VERSION 5.7 ;
BUSBITCHARS "[]" ;
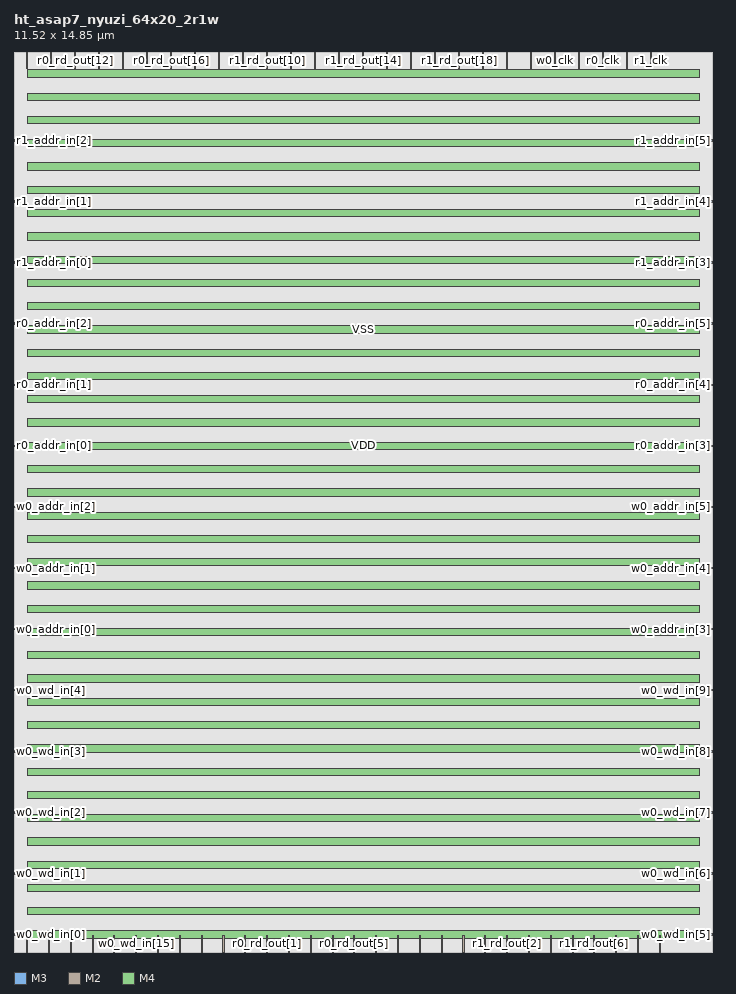
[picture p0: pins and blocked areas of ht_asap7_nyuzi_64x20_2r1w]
MACRO ht_asap7_nyuzi_64x20_2r1w
  FOREIGN ht_asap7_nyuzi_64x20_2r1w 0 0 ;
  SYMMETRY X Y R90 ;
  SIZE 11.520 BY 14.850 ;
  CLASS BLOCK ;
  PIN w0_wd_in[0]
    DIRECTION INPUT ;
    USE SIGNAL ;
    SHAPE ABUTMENT ;
    PORT
      LAYER M3 ;
      RECT 0.000 0.276 0.072 0.300 ;
    END
  END w0_wd_in[0]
  PIN w0_wd_in[1]
    DIRECTION INPUT ;
    USE SIGNAL ;
    SHAPE ABUTMENT ;
    PORT
      LAYER M3 ;
      RECT 0.000 1.284 0.072 1.308 ;
    END
  END w0_wd_in[1]
  PIN w0_wd_in[2]
    DIRECTION INPUT ;
    USE SIGNAL ;
    SHAPE ABUTMENT ;
    PORT
      LAYER M3 ;
      RECT 0.000 2.292 0.072 2.316 ;
    END
  END w0_wd_in[2]
  PIN w0_wd_in[3]
    DIRECTION INPUT ;
    USE SIGNAL ;
    SHAPE ABUTMENT ;
    PORT
      LAYER M3 ;
      RECT 0.000 3.300 0.072 3.324 ;
    END
  END w0_wd_in[3]
  PIN w0_wd_in[4]
    DIRECTION INPUT ;
    USE SIGNAL ;
    SHAPE ABUTMENT ;
    PORT
      LAYER M3 ;
      RECT 0.000 4.308 0.072 4.332 ;
    END
  END w0_wd_in[4]
  PIN w0_wd_in[5]
    DIRECTION INPUT ;
    USE SIGNAL ;
    SHAPE ABUTMENT ;
    PORT
      LAYER M3 ;
      RECT 11.448 0.276 11.520 0.300 ;
    END
  END w0_wd_in[5]
  PIN w0_wd_in[6]
    DIRECTION INPUT ;
    USE SIGNAL ;
    SHAPE ABUTMENT ;
    PORT
      LAYER M3 ;
      RECT 11.448 1.284 11.520 1.308 ;
    END
  END w0_wd_in[6]
  PIN w0_wd_in[7]
    DIRECTION INPUT ;
    USE SIGNAL ;
    SHAPE ABUTMENT ;
    PORT
      LAYER M3 ;
      RECT 11.448 2.292 11.520 2.316 ;
    END
  END w0_wd_in[7]
  PIN w0_wd_in[8]
    DIRECTION INPUT ;
    USE SIGNAL ;
    SHAPE ABUTMENT ;
    PORT
      LAYER M3 ;
      RECT 11.448 3.300 11.520 3.324 ;
    END
  END w0_wd_in[8]
  PIN w0_wd_in[9]
    DIRECTION INPUT ;
    USE SIGNAL ;
    SHAPE ABUTMENT ;
    PORT
      LAYER M3 ;
      RECT 11.448 4.308 11.520 4.332 ;
    END
  END w0_wd_in[9]
  PIN w0_wd_in[10]
    DIRECTION INPUT ;
    USE SIGNAL ;
    SHAPE ABUTMENT ;
    PORT
      LAYER M2 ;
      RECT 0.207 0.000 0.225 0.270 ;
    END
  END w0_wd_in[10]
  PIN w0_wd_in[11]
    DIRECTION INPUT ;
    USE SIGNAL ;
    SHAPE ABUTMENT ;
    PORT
      LAYER M2 ;
      RECT 0.567 0.000 0.585 0.270 ;
    END
  END w0_wd_in[11]
  PIN w0_wd_in[12]
    DIRECTION INPUT ;
    USE SIGNAL ;
    SHAPE ABUTMENT ;
    PORT
      LAYER M2 ;
      RECT 0.927 0.000 0.945 0.270 ;
    END
  END w0_wd_in[12]
  PIN w0_wd_in[13]
    DIRECTION INPUT ;
    USE SIGNAL ;
    SHAPE ABUTMENT ;
    PORT
      LAYER M2 ;
      RECT 1.287 0.000 1.305 0.270 ;
    END
  END w0_wd_in[13]
  PIN w0_wd_in[14]
    DIRECTION INPUT ;
    USE SIGNAL ;
    SHAPE ABUTMENT ;
    PORT
      LAYER M2 ;
      RECT 1.647 0.000 1.665 0.270 ;
    END
  END w0_wd_in[14]
  PIN w0_wd_in[15]
    DIRECTION INPUT ;
    USE SIGNAL ;
    SHAPE ABUTMENT ;
    PORT
      LAYER M2 ;
      RECT 2.007 0.000 2.025 0.270 ;
    END
  END w0_wd_in[15]
  PIN w0_wd_in[16]
    DIRECTION INPUT ;
    USE SIGNAL ;
    SHAPE ABUTMENT ;
    PORT
      LAYER M2 ;
      RECT 2.367 0.000 2.385 0.270 ;
    END
  END w0_wd_in[16]
  PIN w0_wd_in[17]
    DIRECTION INPUT ;
    USE SIGNAL ;
    SHAPE ABUTMENT ;
    PORT
      LAYER M2 ;
      RECT 2.727 0.000 2.745 0.270 ;
    END
  END w0_wd_in[17]
  PIN w0_wd_in[18]
    DIRECTION INPUT ;
    USE SIGNAL ;
    SHAPE ABUTMENT ;
    PORT
      LAYER M2 ;
      RECT 3.087 0.000 3.105 0.270 ;
    END
  END w0_wd_in[18]
  PIN w0_wd_in[19]
    DIRECTION INPUT ;
    USE SIGNAL ;
    SHAPE ABUTMENT ;
    PORT
      LAYER M2 ;
      RECT 3.447 0.000 3.465 0.270 ;
    END
  END w0_wd_in[19]
  PIN r0_rd_out[0]
    DIRECTION OUTPUT ;
    USE SIGNAL ;
    SHAPE ABUTMENT ;
    PORT
      LAYER M2 ;
      RECT 3.807 0.000 3.825 0.270 ;
    END
  END r0_rd_out[0]
  PIN r0_rd_out[1]
    DIRECTION OUTPUT ;
    USE SIGNAL ;
    SHAPE ABUTMENT ;
    PORT
      LAYER M2 ;
      RECT 4.167 0.000 4.185 0.270 ;
    END
  END r0_rd_out[1]
  PIN r0_rd_out[2]
    DIRECTION OUTPUT ;
    USE SIGNAL ;
    SHAPE ABUTMENT ;
    PORT
      LAYER M2 ;
      RECT 4.527 0.000 4.545 0.270 ;
    END
  END r0_rd_out[2]
  PIN r0_rd_out[3]
    DIRECTION OUTPUT ;
    USE SIGNAL ;
    SHAPE ABUTMENT ;
    PORT
      LAYER M2 ;
      RECT 4.887 0.000 4.905 0.270 ;
    END
  END r0_rd_out[3]
  PIN r0_rd_out[4]
    DIRECTION OUTPUT ;
    USE SIGNAL ;
    SHAPE ABUTMENT ;
    PORT
      LAYER M2 ;
      RECT 5.247 0.000 5.265 0.270 ;
    END
  END r0_rd_out[4]
  PIN r0_rd_out[5]
    DIRECTION OUTPUT ;
    USE SIGNAL ;
    SHAPE ABUTMENT ;
    PORT
      LAYER M2 ;
      RECT 5.607 0.000 5.625 0.270 ;
    END
  END r0_rd_out[5]
  PIN r0_rd_out[6]
    DIRECTION OUTPUT ;
    USE SIGNAL ;
    SHAPE ABUTMENT ;
    PORT
      LAYER M2 ;
      RECT 5.967 0.000 5.985 0.270 ;
    END
  END r0_rd_out[6]
  PIN r0_rd_out[7]
    DIRECTION OUTPUT ;
    USE SIGNAL ;
    SHAPE ABUTMENT ;
    PORT
      LAYER M2 ;
      RECT 6.327 0.000 6.345 0.270 ;
    END
  END r0_rd_out[7]
  PIN r0_rd_out[8]
    DIRECTION OUTPUT ;
    USE SIGNAL ;
    SHAPE ABUTMENT ;
    PORT
      LAYER M2 ;
      RECT 6.687 0.000 6.705 0.270 ;
    END
  END r0_rd_out[8]
  PIN r0_rd_out[9]
    DIRECTION OUTPUT ;
    USE SIGNAL ;
    SHAPE ABUTMENT ;
    PORT
      LAYER M2 ;
      RECT 7.047 0.000 7.065 0.270 ;
    END
  END r0_rd_out[9]
  PIN r0_rd_out[10]
    DIRECTION OUTPUT ;
    USE SIGNAL ;
    SHAPE ABUTMENT ;
    PORT
      LAYER M2 ;
      RECT 0.207 14.580 0.225 14.850 ;
    END
  END r0_rd_out[10]
  PIN r0_rd_out[11]
    DIRECTION OUTPUT ;
    USE SIGNAL ;
    SHAPE ABUTMENT ;
    PORT
      LAYER M2 ;
      RECT 0.603 14.580 0.621 14.850 ;
    END
  END r0_rd_out[11]
  PIN r0_rd_out[12]
    DIRECTION OUTPUT ;
    USE SIGNAL ;
    SHAPE ABUTMENT ;
    PORT
      LAYER M2 ;
      RECT 0.999 14.580 1.017 14.850 ;
    END
  END r0_rd_out[12]
  PIN r0_rd_out[13]
    DIRECTION OUTPUT ;
    USE SIGNAL ;
    SHAPE ABUTMENT ;
    PORT
      LAYER M2 ;
      RECT 1.395 14.580 1.413 14.850 ;
    END
  END r0_rd_out[13]
  PIN r0_rd_out[14]
    DIRECTION OUTPUT ;
    USE SIGNAL ;
    SHAPE ABUTMENT ;
    PORT
      LAYER M2 ;
      RECT 1.791 14.580 1.809 14.850 ;
    END
  END r0_rd_out[14]
  PIN r0_rd_out[15]
    DIRECTION OUTPUT ;
    USE SIGNAL ;
    SHAPE ABUTMENT ;
    PORT
      LAYER M2 ;
      RECT 2.187 14.580 2.205 14.850 ;
    END
  END r0_rd_out[15]
  PIN r0_rd_out[16]
    DIRECTION OUTPUT ;
    USE SIGNAL ;
    SHAPE ABUTMENT ;
    PORT
      LAYER M2 ;
      RECT 2.583 14.580 2.601 14.850 ;
    END
  END r0_rd_out[16]
  PIN r0_rd_out[17]
    DIRECTION OUTPUT ;
    USE SIGNAL ;
    SHAPE ABUTMENT ;
    PORT
      LAYER M2 ;
      RECT 2.979 14.580 2.997 14.850 ;
    END
  END r0_rd_out[17]
  PIN r0_rd_out[18]
    DIRECTION OUTPUT ;
    USE SIGNAL ;
    SHAPE ABUTMENT ;
    PORT
      LAYER M2 ;
      RECT 3.375 14.580 3.393 14.850 ;
    END
  END r0_rd_out[18]
  PIN r0_rd_out[19]
    DIRECTION OUTPUT ;
    USE SIGNAL ;
    SHAPE ABUTMENT ;
    PORT
      LAYER M2 ;
      RECT 3.771 14.580 3.789 14.850 ;
    END
  END r0_rd_out[19]
  PIN r1_rd_out[0]
    DIRECTION OUTPUT ;
    USE SIGNAL ;
    SHAPE ABUTMENT ;
    PORT
      LAYER M2 ;
      RECT 7.407 0.000 7.425 0.270 ;
    END
  END r1_rd_out[0]
  PIN r1_rd_out[1]
    DIRECTION OUTPUT ;
    USE SIGNAL ;
    SHAPE ABUTMENT ;
    PORT
      LAYER M2 ;
      RECT 7.767 0.000 7.785 0.270 ;
    END
  END r1_rd_out[1]
  PIN r1_rd_out[2]
    DIRECTION OUTPUT ;
    USE SIGNAL ;
    SHAPE ABUTMENT ;
    PORT
      LAYER M2 ;
      RECT 8.127 0.000 8.145 0.270 ;
    END
  END r1_rd_out[2]
  PIN r1_rd_out[3]
    DIRECTION OUTPUT ;
    USE SIGNAL ;
    SHAPE ABUTMENT ;
    PORT
      LAYER M2 ;
      RECT 8.487 0.000 8.505 0.270 ;
    END
  END r1_rd_out[3]
  PIN r1_rd_out[4]
    DIRECTION OUTPUT ;
    USE SIGNAL ;
    SHAPE ABUTMENT ;
    PORT
      LAYER M2 ;
      RECT 8.847 0.000 8.865 0.270 ;
    END
  END r1_rd_out[4]
  PIN r1_rd_out[5]
    DIRECTION OUTPUT ;
    USE SIGNAL ;
    SHAPE ABUTMENT ;
    PORT
      LAYER M2 ;
      RECT 9.207 0.000 9.225 0.270 ;
    END
  END r1_rd_out[5]
  PIN r1_rd_out[6]
    DIRECTION OUTPUT ;
    USE SIGNAL ;
    SHAPE ABUTMENT ;
    PORT
      LAYER M2 ;
      RECT 9.567 0.000 9.585 0.270 ;
    END
  END r1_rd_out[6]
  PIN r1_rd_out[7]
    DIRECTION OUTPUT ;
    USE SIGNAL ;
    SHAPE ABUTMENT ;
    PORT
      LAYER M2 ;
      RECT 9.927 0.000 9.945 0.270 ;
    END
  END r1_rd_out[7]
  PIN r1_rd_out[8]
    DIRECTION OUTPUT ;
    USE SIGNAL ;
    SHAPE ABUTMENT ;
    PORT
      LAYER M2 ;
      RECT 10.287 0.000 10.305 0.270 ;
    END
  END r1_rd_out[8]
  PIN r1_rd_out[9]
    DIRECTION OUTPUT ;
    USE SIGNAL ;
    SHAPE ABUTMENT ;
    PORT
      LAYER M2 ;
      RECT 10.647 0.000 10.665 0.270 ;
    END
  END r1_rd_out[9]
  PIN r1_rd_out[10]
    DIRECTION OUTPUT ;
    USE SIGNAL ;
    SHAPE ABUTMENT ;
    PORT
      LAYER M2 ;
      RECT 4.167 14.580 4.185 14.850 ;
    END
  END r1_rd_out[10]
  PIN r1_rd_out[11]
    DIRECTION OUTPUT ;
    USE SIGNAL ;
    SHAPE ABUTMENT ;
    PORT
      LAYER M2 ;
      RECT 4.563 14.580 4.581 14.850 ;
    END
  END r1_rd_out[11]
  PIN r1_rd_out[12]
    DIRECTION OUTPUT ;
    USE SIGNAL ;
    SHAPE ABUTMENT ;
    PORT
      LAYER M2 ;
      RECT 4.959 14.580 4.977 14.850 ;
    END
  END r1_rd_out[12]
  PIN r1_rd_out[13]
    DIRECTION OUTPUT ;
    USE SIGNAL ;
    SHAPE ABUTMENT ;
    PORT
      LAYER M2 ;
      RECT 5.355 14.580 5.373 14.850 ;
    END
  END r1_rd_out[13]
  PIN r1_rd_out[14]
    DIRECTION OUTPUT ;
    USE SIGNAL ;
    SHAPE ABUTMENT ;
    PORT
      LAYER M2 ;
      RECT 5.751 14.580 5.769 14.850 ;
    END
  END r1_rd_out[14]
  PIN r1_rd_out[15]
    DIRECTION OUTPUT ;
    USE SIGNAL ;
    SHAPE ABUTMENT ;
    PORT
      LAYER M2 ;
      RECT 6.147 14.580 6.165 14.850 ;
    END
  END r1_rd_out[15]
  PIN r1_rd_out[16]
    DIRECTION OUTPUT ;
    USE SIGNAL ;
    SHAPE ABUTMENT ;
    PORT
      LAYER M2 ;
      RECT 6.543 14.580 6.561 14.850 ;
    END
  END r1_rd_out[16]
  PIN r1_rd_out[17]
    DIRECTION OUTPUT ;
    USE SIGNAL ;
    SHAPE ABUTMENT ;
    PORT
      LAYER M2 ;
      RECT 6.939 14.580 6.957 14.850 ;
    END
  END r1_rd_out[17]
  PIN r1_rd_out[18]
    DIRECTION OUTPUT ;
    USE SIGNAL ;
    SHAPE ABUTMENT ;
    PORT
      LAYER M2 ;
      RECT 7.335 14.580 7.353 14.850 ;
    END
  END r1_rd_out[18]
  PIN r1_rd_out[19]
    DIRECTION OUTPUT ;
    USE SIGNAL ;
    SHAPE ABUTMENT ;
    PORT
      LAYER M2 ;
      RECT 7.731 14.580 7.749 14.850 ;
    END
  END r1_rd_out[19]
  PIN w0_addr_in[0]
    DIRECTION INPUT ;
    USE SIGNAL ;
    SHAPE ABUTMENT ;
    PORT
      LAYER M3 ;
      RECT 0.000 5.316 0.072 5.340 ;
    END
  END w0_addr_in[0]
  PIN w0_addr_in[1]
    DIRECTION INPUT ;
    USE SIGNAL ;
    SHAPE ABUTMENT ;
    PORT
      LAYER M3 ;
      RECT 0.000 6.324 0.072 6.348 ;
    END
  END w0_addr_in[1]
  PIN w0_addr_in[2]
    DIRECTION INPUT ;
    USE SIGNAL ;
    SHAPE ABUTMENT ;
    PORT
      LAYER M3 ;
      RECT 0.000 7.332 0.072 7.356 ;
    END
  END w0_addr_in[2]
  PIN w0_addr_in[3]
    DIRECTION INPUT ;
    USE SIGNAL ;
    SHAPE ABUTMENT ;
    PORT
      LAYER M3 ;
      RECT 11.448 5.316 11.520 5.340 ;
    END
  END w0_addr_in[3]
  PIN w0_addr_in[4]
    DIRECTION INPUT ;
    USE SIGNAL ;
    SHAPE ABUTMENT ;
    PORT
      LAYER M3 ;
      RECT 11.448 6.324 11.520 6.348 ;
    END
  END w0_addr_in[4]
  PIN w0_addr_in[5]
    DIRECTION INPUT ;
    USE SIGNAL ;
    SHAPE ABUTMENT ;
    PORT
      LAYER M3 ;
      RECT 11.448 7.332 11.520 7.356 ;
    END
  END w0_addr_in[5]
  PIN r0_addr_in[0]
    DIRECTION INPUT ;
    USE SIGNAL ;
    SHAPE ABUTMENT ;
    PORT
      LAYER M3 ;
      RECT 0.000 8.340 0.072 8.364 ;
    END
  END r0_addr_in[0]
  PIN r0_addr_in[1]
    DIRECTION INPUT ;
    USE SIGNAL ;
    SHAPE ABUTMENT ;
    PORT
      LAYER M3 ;
      RECT 0.000 9.348 0.072 9.372 ;
    END
  END r0_addr_in[1]
  PIN r0_addr_in[2]
    DIRECTION INPUT ;
    USE SIGNAL ;
    SHAPE ABUTMENT ;
    PORT
      LAYER M3 ;
      RECT 0.000 10.356 0.072 10.380 ;
    END
  END r0_addr_in[2]
  PIN r0_addr_in[3]
    DIRECTION INPUT ;
    USE SIGNAL ;
    SHAPE ABUTMENT ;
    PORT
      LAYER M3 ;
      RECT 11.448 8.340 11.520 8.364 ;
    END
  END r0_addr_in[3]
  PIN r0_addr_in[4]
    DIRECTION INPUT ;
    USE SIGNAL ;
    SHAPE ABUTMENT ;
    PORT
      LAYER M3 ;
      RECT 11.448 9.348 11.520 9.372 ;
    END
  END r0_addr_in[4]
  PIN r0_addr_in[5]
    DIRECTION INPUT ;
    USE SIGNAL ;
    SHAPE ABUTMENT ;
    PORT
      LAYER M3 ;
      RECT 11.448 10.356 11.520 10.380 ;
    END
  END r0_addr_in[5]
  PIN r1_addr_in[0]
    DIRECTION INPUT ;
    USE SIGNAL ;
    SHAPE ABUTMENT ;
    PORT
      LAYER M3 ;
      RECT 0.000 11.364 0.072 11.388 ;
    END
  END r1_addr_in[0]
  PIN r1_addr_in[1]
    DIRECTION INPUT ;
    USE SIGNAL ;
    SHAPE ABUTMENT ;
    PORT
      LAYER M3 ;
      RECT 0.000 12.372 0.072 12.396 ;
    END
  END r1_addr_in[1]
  PIN r1_addr_in[2]
    DIRECTION INPUT ;
    USE SIGNAL ;
    SHAPE ABUTMENT ;
    PORT
      LAYER M3 ;
      RECT 0.000 13.380 0.072 13.404 ;
    END
  END r1_addr_in[2]
  PIN r1_addr_in[3]
    DIRECTION INPUT ;
    USE SIGNAL ;
    SHAPE ABUTMENT ;
    PORT
      LAYER M3 ;
      RECT 11.448 11.364 11.520 11.388 ;
    END
  END r1_addr_in[3]
  PIN r1_addr_in[4]
    DIRECTION INPUT ;
    USE SIGNAL ;
    SHAPE ABUTMENT ;
    PORT
      LAYER M3 ;
      RECT 11.448 12.372 11.520 12.396 ;
    END
  END r1_addr_in[4]
  PIN r1_addr_in[5]
    DIRECTION INPUT ;
    USE SIGNAL ;
    SHAPE ABUTMENT ;
    PORT
      LAYER M3 ;
      RECT 11.448 13.380 11.520 13.404 ;
    END
  END r1_addr_in[5]
  PIN w0_we_in
    DIRECTION INPUT ;
    USE SIGNAL ;
    SHAPE ABUTMENT ;
    PORT
      LAYER M2 ;
      RECT 8.127 14.580 8.145 14.850 ;
    END
  END w0_we_in
  PIN w0_ce_in
    DIRECTION INPUT ;
    USE SIGNAL ;
    SHAPE ABUTMENT ;
    PORT
      LAYER M2 ;
      RECT 8.523 14.580 8.541 14.850 ;
    END
  END w0_ce_in
  PIN w0_clk
    DIRECTION INPUT ;
    USE SIGNAL ;
    SHAPE ABUTMENT ;
    PORT
      LAYER M2 ;
      RECT 8.919 14.580 8.937 14.850 ;
    END
  END w0_clk
  PIN r0_ce_in
    DIRECTION INPUT ;
    USE SIGNAL ;
    SHAPE ABUTMENT ;
    PORT
      LAYER M2 ;
      RECT 9.315 14.580 9.333 14.850 ;
    END
  END r0_ce_in
  PIN r0_clk
    DIRECTION INPUT ;
    USE SIGNAL ;
    SHAPE ABUTMENT ;
    PORT
      LAYER M2 ;
      RECT 9.711 14.580 9.729 14.850 ;
    END
  END r0_clk
  PIN r1_ce_in
    DIRECTION INPUT ;
    USE SIGNAL ;
    SHAPE ABUTMENT ;
    PORT
      LAYER M2 ;
      RECT 10.107 14.580 10.125 14.850 ;
    END
  END r1_ce_in
  PIN r1_clk
    DIRECTION INPUT ;
    USE SIGNAL ;
    SHAPE ABUTMENT ;
    PORT
      LAYER M2 ;
      RECT 10.503 14.580 10.521 14.850 ;
    END
  END r1_clk
  PIN VSS
    DIRECTION INOUT ;
    USE GROUND ;
    PORT
      LAYER M4 ;
      RECT 0.216 0.228 11.304 0.348 ;
      RECT 0.216 0.996 11.304 1.116 ;
      RECT 0.216 1.764 11.304 1.884 ;
      RECT 0.216 2.532 11.304 2.652 ;
      RECT 0.216 3.300 11.304 3.420 ;
      RECT 0.216 4.068 11.304 4.188 ;
      RECT 0.216 4.836 11.304 4.956 ;
      RECT 0.216 5.604 11.304 5.724 ;
      RECT 0.216 6.372 11.304 6.492 ;
      RECT 0.216 7.140 11.304 7.260 ;
      RECT 0.216 7.908 11.304 8.028 ;
      RECT 0.216 8.676 11.304 8.796 ;
      RECT 0.216 9.444 11.304 9.564 ;
      RECT 0.216 10.212 11.304 10.332 ;
      RECT 0.216 10.980 11.304 11.100 ;
      RECT 0.216 11.748 11.304 11.868 ;
      RECT 0.216 12.516 11.304 12.636 ;
      RECT 0.216 13.284 11.304 13.404 ;
      RECT 0.216 14.052 11.304 14.172 ;
    END
  END VSS
  PIN VDD
    DIRECTION INOUT ;
    USE POWER ;
    PORT
      LAYER M4 ;
      RECT 0.216 0.612 11.304 0.732 ;
      RECT 0.216 1.380 11.304 1.500 ;
      RECT 0.216 2.148 11.304 2.268 ;
      RECT 0.216 2.916 11.304 3.036 ;
      RECT 0.216 3.684 11.304 3.804 ;
      RECT 0.216 4.452 11.304 4.572 ;
      RECT 0.216 5.220 11.304 5.340 ;
      RECT 0.216 5.988 11.304 6.108 ;
      RECT 0.216 6.756 11.304 6.876 ;
      RECT 0.216 7.524 11.304 7.644 ;
      RECT 0.216 8.292 11.304 8.412 ;
      RECT 0.216 9.060 11.304 9.180 ;
      RECT 0.216 9.828 11.304 9.948 ;
      RECT 0.216 10.596 11.304 10.716 ;
      RECT 0.216 11.364 11.304 11.484 ;
      RECT 0.216 12.132 11.304 12.252 ;
      RECT 0.216 12.900 11.304 13.020 ;
      RECT 0.216 13.668 11.304 13.788 ;
      RECT 0.216 14.436 11.304 14.556 ;
    END
  END VDD
  OBS
    LAYER M1 ;
    RECT 0 0 11.520 14.850 ;
    LAYER M2 ;
    RECT 0 0 11.520 14.850 ;
    LAYER M3 ;
    RECT 0 0 11.520 14.850 ;
    LAYER M4 ;
    RECT 0 0 11.520 14.850 ;
  END
END ht_asap7_nyuzi_64x20_2r1w

END LIBRARY
